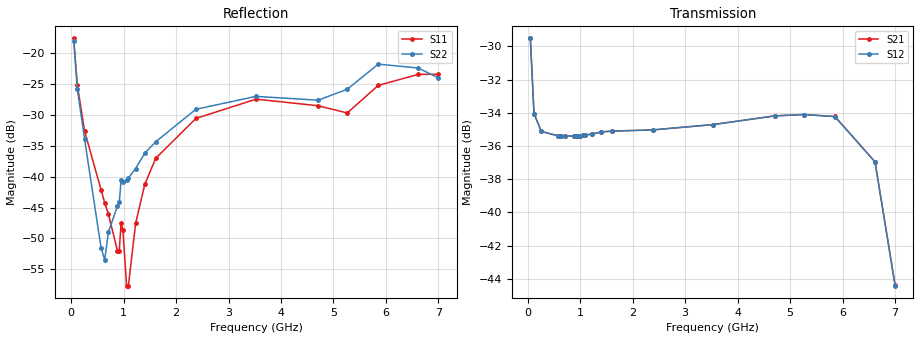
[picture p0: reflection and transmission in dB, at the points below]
! Integrated Device Technology
! Corporate Headquarters
! 6024 Silver Creek Valley Road
! San Jose, CA 95138  USA
! Phone:  1-408-284-8200
! Toll Free:  1-800-223-1366
! Webpage:  http://www.idt.com/
! Timing and RF Division
! 515 Groton Road, Suite 102
! Westford, MA 01886-6024
! Device:  F2258
! Description: Voltage Variable RF Attenuator
! Frequency:  50.0 -  6000.00 MHz
! Package:  3x3 mm Thin QFN Plastic Package: 16 pin
! Ports:  2 RF, 2 DC
!  Pin  1  = NC
!  Pin  2  = NC
!  Pin  3  = RF2  = Port 2
!  Pin  4  = GND
!  Pin  5  = Vdd
!  Pin  6  = NC
!  Pin  7  = VCTRL
!  Pin  8  = NC
!  Pin  9  = GND
!  Pin 10  = RF1  = Port 1
!  Pin 11  = NC
!  Pin 12  = NC
!  Pin 13  = NC
!  Pin 14  = NC
!  Pin 15  = NC
!  Pin 16  = NC
! Vcntrl:  2.230 Volts
! Vdd:  +3.300 Volts
! Current:  1.150 mA
! Data:  The device was measured on a the F2258 evaluation board which has
!  individual transmission lines to the RF pins.  Data was collected
!  using a calibrated network analyzer.  The evaluation board was
!  de-embedded using a TRL calibration technique.
!  The reference plane is the edge of the package pin.
! Misc:  SN 10
!  Action Tracker AT0285
! Date Measured:  2014-12-10
! Date:  2016-01-13  MJV
! Note:
!  Integrated Device Technology supplies this data as a sample of measured
!  data at the package pin for this product.  Your particular data for this
!  product may vary.
!  Data was taken at 25 degrees C.
!  Integrated Device Technology reserves the right to change this data at anytime.
!Freq_(GHz)  S11M_(dB)  S11P_(deg)  S21M_(dB)  S21P_(deg)  S12M_(dB)  S12P_(deg)  S22M_(dB)  S22P_(deg)
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# GHz S dB R 50
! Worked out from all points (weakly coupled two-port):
!   201 points, 50 MHz to 7 GHz, reference 50 ohm
!   highest |S21| = -29.51 dB at 50 MHz (marker M1); lowest = -44.4 dB at 7 GHz (marker M2)
!   lowest |S11| = -57.7 dB at 1.058 GHz (marker M3), VSWR 1.00, Z = 49.9 + j0.0573 ohm
!   |S11| at or under -10 dB: start of sweep to end of sweep
!   |S22| runs from -53.5 to -17.9 dB; largest |S21 - S12| = 8.2e-05
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0.05  -17.55 -111.0  -29.51 -68.3  -29.51 -68.3  -17.90 -111.1
0.1195  -25.12 -106.9  -34.04 -36.8  -34.04 -36.8  -25.75 -106.1
0.2585  -32.62 -111.9  -35.12 -18.8  -35.12 -18.8  -33.94 -110.1
0.57125  -42.10 -124.9  -35.38 -10.4  -35.38 -10.3  -51.50 -154.6
0.64075  -44.21 -127.8  -35.39 -9.7  -35.40 -9.7  -53.50 165.0
0.71025  -46.00 -137.8  -35.40 -9.2  -35.40 -9.2  -49.04 123.5
0.884  -52.00 166.1  -35.39 -8.4  -35.39 -8.4  -44.74 108.8
0.91875  -51.97 150.4  -35.39 -8.3  -35.39 -8.4  -44.13 107.0
0.9535  -47.52 -162.6  -35.40 -8.3  -35.40 -8.2  -40.52 117.0
0.98825  -48.71 -173.7  -35.38 -8.1  -35.38 -8.1  -40.83 114.5
1.05775  -57.67 154.0  -35.36 -8.0  -35.36 -8.0  -40.51 98.7
1.0925  -57.65 119.6  -35.34 -7.9  -35.35 -7.9  -40.21 94.9
1.2315  -47.51 46.9  -35.27 -8.0  -35.27 -8.0  -38.66 73.6
1.40525  -41.22 33.8  -35.15 -8.6  -35.15 -8.6  -36.17 61.6
1.61375  -37.00 32.8  -35.10 -9.6  -35.10 -9.6  -34.32 49.9
2.37825  -30.54 48.2  -35.03 -13.3  -35.03 -13.2  -29.05 41.6
3.525  -27.41 91.6  -34.71 -19.7  -34.71 -19.7  -26.96 66.2
4.7065  -28.48 95.6  -34.18 -28.8  -34.19 -28.9  -27.58 57.7
5.2625  -29.65 54.4  -34.10 -35.0  -34.10 -35.0  -25.81 20.2
5.85325  -25.18 29.8  -34.22 -45.6  -34.23 -45.6  -21.73 -3.2
6.61775  -23.39 49.8  -36.95 -68.7  -36.96 -68.7  -22.36 -44.9
7  -23.37 84.4  -44.37 -61.9  -44.42 -61.2  -23.97 -129.7
